! (c) 2009  Infineon Technologies AG, Munich
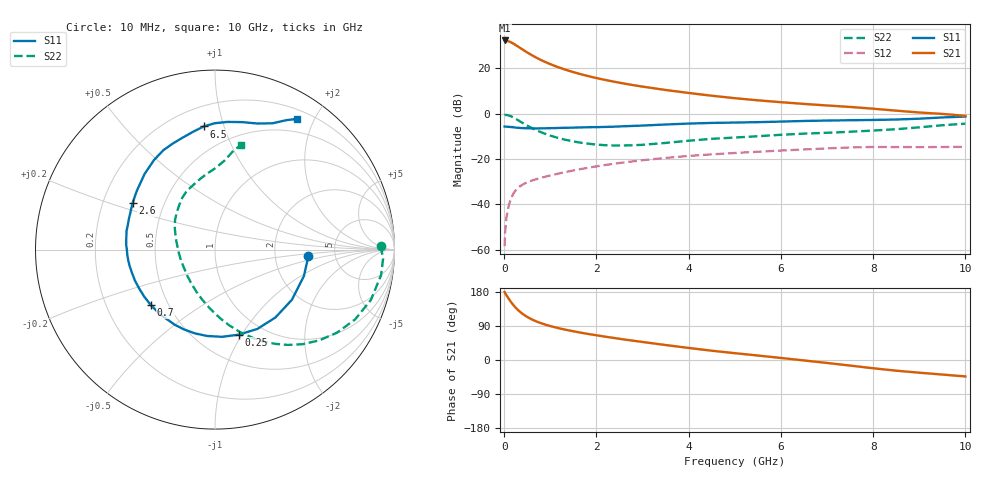
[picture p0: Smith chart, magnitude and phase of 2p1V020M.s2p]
! Infineon Technologies  Discrete & RF Semiconductors
! BFP420
! VCE =  1.0 V,  IC =  20 mA
! Common Emitter S-Parameters:  Nov 2009
# GHz  S  MA  R  50
!  f  S11  S21  S12  S22
! GHz  MAG  ANG  MAG  ANG  MAG  ANG  MAG  ANG
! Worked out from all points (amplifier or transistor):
!   46 points, 10 MHz to 10 GHz, reference 50 ohm
!   highest |S21| = 32.2 dB at 10 MHz (marker M1)
!   |S21| within 3 dB of that: start of sweep to 325.2 MHz
!   unconditionally stable (mu >= 1): start of sweep to 10.4 MHz; 1.716 GHz to end of sweep
!   at 300 MHz: K = 0.33, MSG = 31.2 dB, |S12| = -32.8 dB
!   at 1.7 GHz: K = 1.00, MSG = 20.7 dB, |S12| = -24.3 dB
!   at 10 GHz: K = 1.06, MAG = 5.3 dB, |S12| = -14.7 dB
!   lowest NFmin = 1.23 dB at 900 MHz
!   S11 on the Smith chart (normalised r, x): 10 MHz: 3.12, -0.29; 250 MHz: 0.78, -0.97; 700 MHz: 0.40, -0.32; 2.6 GHz: 0.33, +0.23; 6.5 GHz: 0.33, +0.86; 10 GHz: 0.31, +1.77
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0.01  0.5185 -3.8  40.97 179.4  0.0012 97.0  0.9238 1.2
0.02  0.5183 -7.0  40.24 176.5  0.0023 89.9  0.9378 -3.1
0.05  0.5168 -16.6  40.05 170.7  0.0051 85.5  0.9364 -8.7
0.1  0.5116 -33.1  39.08 161.5  0.0095 78.3  0.9127 -17.9
0.15  0.5064 -48.3  37.17 152.8  0.0136 72.7  0.8721 -26.5
0.2  0.5011 -61.8  34.93 145.0  0.0173 67.8  0.8227 -34.2
0.25  0.4921 -74.4  32.43 138.0  0.0204 63.8  0.7706 -41.0
0.35  0.4833 -95.3  27.92 126.6  0.0253 58.1  0.6687 -52.6
0.45  0.4771 -111.3  23.99 117.5  0.029 54.4  0.582 -61.8
0.6  0.4729 -129.5  19.41 107.1  0.0334 51.4  0.4812 -73.0
0.7  0.4728 -138.9  17.07 101.7  0.036 50.5  0.4305 -79.2
0.9  0.4749 -153.2  13.62 93.1  0.0409 49.6  0.3559 -90.1
1.1  0.48 -164.0  11.23 86.4  0.0458 49.3  0.3051 -99.9
1.4  0.4895 -176.4  8.816 78.2  0.0533 48.7  0.256 -114.0
1.7  0.4978 173.6  7.223 71.3  0.061 47.7  0.2261 -127.2
2.6  0.5269 150.7  4.601 54.2  0.0841 42.2  0.1988 -165.0
3.5  0.576 132.9  3.32 39.5  0.1056 34.7  0.2262 164.5
5.5  0.6491 106.2  1.964 11.8  0.1445 16.8  0.3178 128.9
6.5  0.689 95.3  1.636 -1.2  0.1623 7.7  0.3625 115.8
7  0.7041 90.1  1.513 -7.8  0.1715 2.8  0.3782 109.1
8.5  0.7413 71.4  1.162 -28.2  0.1834 -14.2  0.4538 89.7
10  0.8612 57.8  0.894 -43.4  0.1851 -25.1  0.6011 76.2
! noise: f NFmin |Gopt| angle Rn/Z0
0.9  1.23  0.16  -154  0.13
1.8  1.51  0.24  -144  0.13
2.4  1.66  0.22  -141  0.15
3  1.69  0.3  -132  0.16
4  1.82  0.42  -115  0.23
5  2.28  0.48  -96  0.37
6  2.65  0.52  -86  0.56
